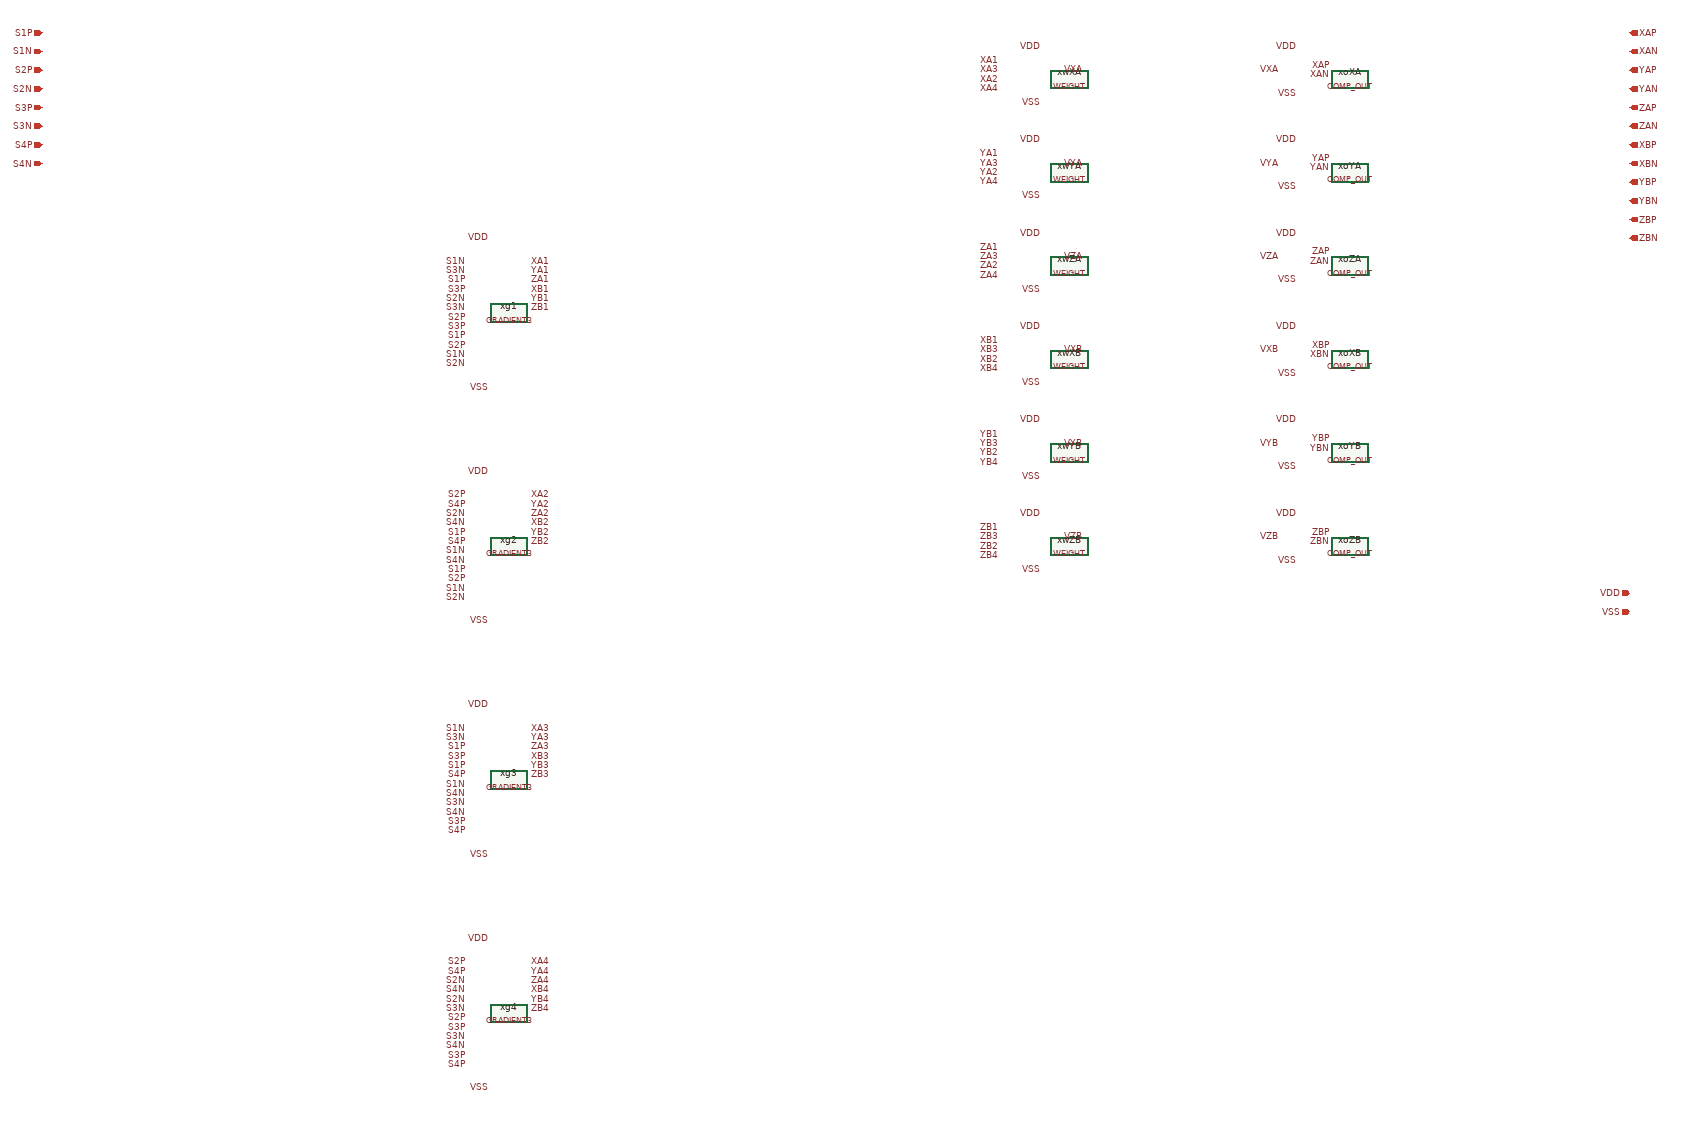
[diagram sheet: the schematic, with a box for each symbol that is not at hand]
v {xschem version=3.4.8RC file_version=1.3}
G {}
K {}
V {}
S {}
F {}
E {}
C {a_zonetic2026/XSCHEM_v2/GRADIENT3.sym} -600 -400 0 0 {name=xg1}
C {devices/lab_pin.sym} -690.0 -510.0 0 0 {name=l1 sig_type=std_logic lab=S1N}
C {devices/lab_pin.sym} -690.0 -490.0 0 0 {name=l2 sig_type=std_logic lab=S3N}
C {devices/lab_pin.sym} -690.0 -470.0 0 0 {name=l3 sig_type=std_logic lab=S1P}
C {devices/lab_pin.sym} -690.0 -450.0 0 0 {name=l4 sig_type=std_logic lab=S3P}
C {devices/lab_pin.sym} -690.0 -430.0 0 0 {name=l5 sig_type=std_logic lab=S2N}
C {devices/lab_pin.sym} -690.0 -410.0 0 0 {name=l6 sig_type=std_logic lab=S3N}
C {devices/lab_pin.sym} -690.0 -390.0 0 0 {name=l7 sig_type=std_logic lab=S2P}
C {devices/lab_pin.sym} -690.0 -370.0 0 0 {name=l8 sig_type=std_logic lab=S3P}
C {devices/lab_pin.sym} -690.0 -350.0 0 0 {name=l9 sig_type=std_logic lab=S1P}
C {devices/lab_pin.sym} -690.0 -330.0 0 0 {name=l10 sig_type=std_logic lab=S2P}
C {devices/lab_pin.sym} -690.0 -310.0 0 0 {name=l11 sig_type=std_logic lab=S1N}
C {devices/lab_pin.sym} -690.0 -290.0 0 0 {name=l12 sig_type=std_logic lab=S2N}
C {devices/lab_pin.sym} -510.0 -510.0 0 0 {name=l13 sig_type=std_logic lab=XA1}
C {devices/lab_pin.sym} -510.0 -490.0 0 0 {name=l14 sig_type=std_logic lab=YA1}
C {devices/lab_pin.sym} -510.0 -470.0 0 0 {name=l15 sig_type=std_logic lab=ZA1}
C {devices/lab_pin.sym} -510.0 -450.0 0 0 {name=l16 sig_type=std_logic lab=XB1}
C {devices/lab_pin.sym} -510.0 -430.0 0 0 {name=l17 sig_type=std_logic lab=YB1}
C {devices/lab_pin.sym} -510.0 -410.0 0 0 {name=l18 sig_type=std_logic lab=ZB1}
C {devices/lab_pin.sym} -640.0 -560.0 0 0 {name=l19 sig_type=std_logic lab=VDD}
C {devices/lab_pin.sym} -640.0 -240.0 0 0 {name=l20 sig_type=std_logic lab=VSS}
C {a_zonetic2026/XSCHEM_v2/GRADIENT3.sym} -600 100 0 0 {name=xg2}
C {devices/lab_pin.sym} -690.0 -10.0 0 0 {name=l21 sig_type=std_logic lab=S2P}
C {devices/lab_pin.sym} -690.0 10.0 0 0 {name=l22 sig_type=std_logic lab=S4P}
C {devices/lab_pin.sym} -690.0 30.0 0 0 {name=l23 sig_type=std_logic lab=S2N}
C {devices/lab_pin.sym} -690.0 50.0 0 0 {name=l24 sig_type=std_logic lab=S4N}
C {devices/lab_pin.sym} -690.0 70.0 0 0 {name=l25 sig_type=std_logic lab=S1P}
C {devices/lab_pin.sym} -690.0 90.0 0 0 {name=l26 sig_type=std_logic lab=S4P}
C {devices/lab_pin.sym} -690.0 110.0 0 0 {name=l27 sig_type=std_logic lab=S1N}
C {devices/lab_pin.sym} -690.0 130.0 0 0 {name=l28 sig_type=std_logic lab=S4N}
C {devices/lab_pin.sym} -690.0 150.0 0 0 {name=l29 sig_type=std_logic lab=S1P}
C {devices/lab_pin.sym} -690.0 170.0 0 0 {name=l30 sig_type=std_logic lab=S2P}
C {devices/lab_pin.sym} -690.0 190.0 0 0 {name=l31 sig_type=std_logic lab=S1N}
C {devices/lab_pin.sym} -690.0 210.0 0 0 {name=l32 sig_type=std_logic lab=S2N}
C {devices/lab_pin.sym} -510.0 -10.0 0 0 {name=l33 sig_type=std_logic lab=XA2}
C {devices/lab_pin.sym} -510.0 10.0 0 0 {name=l34 sig_type=std_logic lab=YA2}
C {devices/lab_pin.sym} -510.0 30.0 0 0 {name=l35 sig_type=std_logic lab=ZA2}
C {devices/lab_pin.sym} -510.0 50.0 0 0 {name=l36 sig_type=std_logic lab=XB2}
C {devices/lab_pin.sym} -510.0 70.0 0 0 {name=l37 sig_type=std_logic lab=YB2}
C {devices/lab_pin.sym} -510.0 90.0 0 0 {name=l38 sig_type=std_logic lab=ZB2}
C {devices/lab_pin.sym} -640.0 -60.0 0 0 {name=l39 sig_type=std_logic lab=VDD}
C {devices/lab_pin.sym} -640.0 260.0 0 0 {name=l40 sig_type=std_logic lab=VSS}
C {a_zonetic2026/XSCHEM_v2/GRADIENT3.sym} -600 600 0 0 {name=xg3}
C {devices/lab_pin.sym} -690.0 490.0 0 0 {name=l41 sig_type=std_logic lab=S1N}
C {devices/lab_pin.sym} -690.0 510.0 0 0 {name=l42 sig_type=std_logic lab=S3N}
C {devices/lab_pin.sym} -690.0 530.0 0 0 {name=l43 sig_type=std_logic lab=S1P}
C {devices/lab_pin.sym} -690.0 550.0 0 0 {name=l44 sig_type=std_logic lab=S3P}
C {devices/lab_pin.sym} -690.0 570.0 0 0 {name=l45 sig_type=std_logic lab=S1P}
C {devices/lab_pin.sym} -690.0 590.0 0 0 {name=l46 sig_type=std_logic lab=S4P}
C {devices/lab_pin.sym} -690.0 610.0 0 0 {name=l47 sig_type=std_logic lab=S1N}
C {devices/lab_pin.sym} -690.0 630.0 0 0 {name=l48 sig_type=std_logic lab=S4N}
C {devices/lab_pin.sym} -690.0 650.0 0 0 {name=l49 sig_type=std_logic lab=S3N}
C {devices/lab_pin.sym} -690.0 670.0 0 0 {name=l50 sig_type=std_logic lab=S4N}
C {devices/lab_pin.sym} -690.0 690.0 0 0 {name=l51 sig_type=std_logic lab=S3P}
C {devices/lab_pin.sym} -690.0 710.0 0 0 {name=l52 sig_type=std_logic lab=S4P}
C {devices/lab_pin.sym} -510.0 490.0 0 0 {name=l53 sig_type=std_logic lab=XA3}
C {devices/lab_pin.sym} -510.0 510.0 0 0 {name=l54 sig_type=std_logic lab=YA3}
C {devices/lab_pin.sym} -510.0 530.0 0 0 {name=l55 sig_type=std_logic lab=ZA3}
C {devices/lab_pin.sym} -510.0 550.0 0 0 {name=l56 sig_type=std_logic lab=XB3}
C {devices/lab_pin.sym} -510.0 570.0 0 0 {name=l57 sig_type=std_logic lab=YB3}
C {devices/lab_pin.sym} -510.0 590.0 0 0 {name=l58 sig_type=std_logic lab=ZB3}
C {devices/lab_pin.sym} -640.0 440.0 0 0 {name=l59 sig_type=std_logic lab=VDD}
C {devices/lab_pin.sym} -640.0 760.0 0 0 {name=l60 sig_type=std_logic lab=VSS}
C {a_zonetic2026/XSCHEM_v2/GRADIENT3.sym} -600 1100 0 0 {name=xg4}
C {devices/lab_pin.sym} -690.0 990.0 0 0 {name=l61 sig_type=std_logic lab=S2P}
C {devices/lab_pin.sym} -690.0 1010.0 0 0 {name=l62 sig_type=std_logic lab=S4P}
C {devices/lab_pin.sym} -690.0 1030.0 0 0 {name=l63 sig_type=std_logic lab=S2N}
C {devices/lab_pin.sym} -690.0 1050.0 0 0 {name=l64 sig_type=std_logic lab=S4N}
C {devices/lab_pin.sym} -690.0 1070.0 0 0 {name=l65 sig_type=std_logic lab=S2N}
C {devices/lab_pin.sym} -690.0 1090.0 0 0 {name=l66 sig_type=std_logic lab=S3N}
C {devices/lab_pin.sym} -690.0 1110.0 0 0 {name=l67 sig_type=std_logic lab=S2P}
C {devices/lab_pin.sym} -690.0 1130.0 0 0 {name=l68 sig_type=std_logic lab=S3P}
C {devices/lab_pin.sym} -690.0 1150.0 0 0 {name=l69 sig_type=std_logic lab=S3N}
C {devices/lab_pin.sym} -690.0 1170.0 0 0 {name=l70 sig_type=std_logic lab=S4N}
C {devices/lab_pin.sym} -690.0 1190.0 0 0 {name=l71 sig_type=std_logic lab=S3P}
C {devices/lab_pin.sym} -690.0 1210.0 0 0 {name=l72 sig_type=std_logic lab=S4P}
C {devices/lab_pin.sym} -510.0 990.0 0 0 {name=l73 sig_type=std_logic lab=XA4}
C {devices/lab_pin.sym} -510.0 1010.0 0 0 {name=l74 sig_type=std_logic lab=YA4}
C {devices/lab_pin.sym} -510.0 1030.0 0 0 {name=l75 sig_type=std_logic lab=ZA4}
C {devices/lab_pin.sym} -510.0 1050.0 0 0 {name=l76 sig_type=std_logic lab=XB4}
C {devices/lab_pin.sym} -510.0 1070.0 0 0 {name=l77 sig_type=std_logic lab=YB4}
C {devices/lab_pin.sym} -510.0 1090.0 0 0 {name=l78 sig_type=std_logic lab=ZB4}
C {devices/lab_pin.sym} -640.0 940.0 0 0 {name=l79 sig_type=std_logic lab=VDD}
C {devices/lab_pin.sym} -640.0 1260.0 0 0 {name=l80 sig_type=std_logic lab=VSS}
C {a_zonetic2026/XSCHEM/WEIGTH/WEIGHT.sym} 600 -900 0 0 {name=xwXA}
C {devices/lab_pin.sym} 540.0 -970.0 0 0 {name=l81 sig_type=std_logic lab=VDD}
C {devices/lab_pin.sym} 540.0 -850.0 0 0 {name=l82 sig_type=std_logic lab=VSS}
C {devices/lab_pin.sym} 630.0 -920.0 0 0 {name=l83 sig_type=std_logic lab=VXA}
C {devices/lab_pin.sym} 450.0 -940.0 0 0 {name=l84 sig_type=std_logic lab=XA1}
C {devices/lab_pin.sym} 450.0 -920.0 0 0 {name=l85 sig_type=std_logic lab=XA3}
C {devices/lab_pin.sym} 450.0 -900.0 0 0 {name=l86 sig_type=std_logic lab=XA2}
C {devices/lab_pin.sym} 450.0 -880.0 0 0 {name=l87 sig_type=std_logic lab=XA4}
C {a_zonetic2026/XSCHEM/WEIGTH/COMP_OUT.sym} 1200 -900 0 0 {name=xoXA}
C {devices/lab_pin.sym} 1090.0 -970.0 0 0 {name=l88 sig_type=std_logic lab=VDD}
C {devices/lab_pin.sym} 1160.0 -930.0 0 0 {name=l89 sig_type=std_logic lab=XAP}
C {devices/lab_pin.sym} 1050.0 -920.0 0 0 {name=l90 sig_type=std_logic lab=VXA}
C {devices/lab_pin.sym} 1160.0 -910.0 0 0 {name=l91 sig_type=std_logic lab=XAN}
C {devices/lab_pin.sym} 1090.0 -870.0 0 0 {name=l92 sig_type=std_logic lab=VSS}
C {a_zonetic2026/XSCHEM/WEIGTH/WEIGHT.sym} 600 -700 0 0 {name=xwYA}
C {devices/lab_pin.sym} 540.0 -770.0 0 0 {name=l93 sig_type=std_logic lab=VDD}
C {devices/lab_pin.sym} 540.0 -650.0 0 0 {name=l94 sig_type=std_logic lab=VSS}
C {devices/lab_pin.sym} 630.0 -720.0 0 0 {name=l95 sig_type=std_logic lab=VYA}
C {devices/lab_pin.sym} 450.0 -740.0 0 0 {name=l96 sig_type=std_logic lab=YA1}
C {devices/lab_pin.sym} 450.0 -720.0 0 0 {name=l97 sig_type=std_logic lab=YA3}
C {devices/lab_pin.sym} 450.0 -700.0 0 0 {name=l98 sig_type=std_logic lab=YA2}
C {devices/lab_pin.sym} 450.0 -680.0 0 0 {name=l99 sig_type=std_logic lab=YA4}
C {a_zonetic2026/XSCHEM/WEIGTH/COMP_OUT.sym} 1200 -700 0 0 {name=xoYA}
C {devices/lab_pin.sym} 1090.0 -770.0 0 0 {name=l100 sig_type=std_logic lab=VDD}
C {devices/lab_pin.sym} 1160.0 -730.0 0 0 {name=l101 sig_type=std_logic lab=YAP}
C {devices/lab_pin.sym} 1050.0 -720.0 0 0 {name=l102 sig_type=std_logic lab=VYA}
C {devices/lab_pin.sym} 1160.0 -710.0 0 0 {name=l103 sig_type=std_logic lab=YAN}
C {devices/lab_pin.sym} 1090.0 -670.0 0 0 {name=l104 sig_type=std_logic lab=VSS}
C {a_zonetic2026/XSCHEM/WEIGTH/WEIGHT.sym} 600 -500 0 0 {name=xwZA}
C {devices/lab_pin.sym} 540.0 -570.0 0 0 {name=l105 sig_type=std_logic lab=VDD}
C {devices/lab_pin.sym} 540.0 -450.0 0 0 {name=l106 sig_type=std_logic lab=VSS}
C {devices/lab_pin.sym} 630.0 -520.0 0 0 {name=l107 sig_type=std_logic lab=VZA}
C {devices/lab_pin.sym} 450.0 -540.0 0 0 {name=l108 sig_type=std_logic lab=ZA1}
C {devices/lab_pin.sym} 450.0 -520.0 0 0 {name=l109 sig_type=std_logic lab=ZA3}
C {devices/lab_pin.sym} 450.0 -500.0 0 0 {name=l110 sig_type=std_logic lab=ZA2}
C {devices/lab_pin.sym} 450.0 -480.0 0 0 {name=l111 sig_type=std_logic lab=ZA4}
C {a_zonetic2026/XSCHEM/WEIGTH/COMP_OUT.sym} 1200 -500 0 0 {name=xoZA}
C {devices/lab_pin.sym} 1090.0 -570.0 0 0 {name=l112 sig_type=std_logic lab=VDD}
C {devices/lab_pin.sym} 1160.0 -530.0 0 0 {name=l113 sig_type=std_logic lab=ZAP}
C {devices/lab_pin.sym} 1050.0 -520.0 0 0 {name=l114 sig_type=std_logic lab=VZA}
C {devices/lab_pin.sym} 1160.0 -510.0 0 0 {name=l115 sig_type=std_logic lab=ZAN}
C {devices/lab_pin.sym} 1090.0 -470.0 0 0 {name=l116 sig_type=std_logic lab=VSS}
C {a_zonetic2026/XSCHEM/WEIGTH/WEIGHT.sym} 600 -300 0 0 {name=xwXB}
C {devices/lab_pin.sym} 540.0 -370.0 0 0 {name=l117 sig_type=std_logic lab=VDD}
C {devices/lab_pin.sym} 540.0 -250.0 0 0 {name=l118 sig_type=std_logic lab=VSS}
C {devices/lab_pin.sym} 630.0 -320.0 0 0 {name=l119 sig_type=std_logic lab=VXB}
C {devices/lab_pin.sym} 450.0 -340.0 0 0 {name=l120 sig_type=std_logic lab=XB1}
C {devices/lab_pin.sym} 450.0 -320.0 0 0 {name=l121 sig_type=std_logic lab=XB3}
C {devices/lab_pin.sym} 450.0 -300.0 0 0 {name=l122 sig_type=std_logic lab=XB2}
C {devices/lab_pin.sym} 450.0 -280.0 0 0 {name=l123 sig_type=std_logic lab=XB4}
C {a_zonetic2026/XSCHEM/WEIGTH/COMP_OUT.sym} 1200 -300 0 0 {name=xoXB}
C {devices/lab_pin.sym} 1090.0 -370.0 0 0 {name=l124 sig_type=std_logic lab=VDD}
C {devices/lab_pin.sym} 1160.0 -330.0 0 0 {name=l125 sig_type=std_logic lab=XBP}
C {devices/lab_pin.sym} 1050.0 -320.0 0 0 {name=l126 sig_type=std_logic lab=VXB}
C {devices/lab_pin.sym} 1160.0 -310.0 0 0 {name=l127 sig_type=std_logic lab=XBN}
C {devices/lab_pin.sym} 1090.0 -270.0 0 0 {name=l128 sig_type=std_logic lab=VSS}
C {a_zonetic2026/XSCHEM/WEIGTH/WEIGHT.sym} 600 -100 0 0 {name=xwYB}
C {devices/lab_pin.sym} 540.0 -170.0 0 0 {name=l129 sig_type=std_logic lab=VDD}
C {devices/lab_pin.sym} 540.0 -50.0 0 0 {name=l130 sig_type=std_logic lab=VSS}
C {devices/lab_pin.sym} 630.0 -120.0 0 0 {name=l131 sig_type=std_logic lab=VYB}
C {devices/lab_pin.sym} 450.0 -140.0 0 0 {name=l132 sig_type=std_logic lab=YB1}
C {devices/lab_pin.sym} 450.0 -120.0 0 0 {name=l133 sig_type=std_logic lab=YB3}
C {devices/lab_pin.sym} 450.0 -100.0 0 0 {name=l134 sig_type=std_logic lab=YB2}
C {devices/lab_pin.sym} 450.0 -80.0 0 0 {name=l135 sig_type=std_logic lab=YB4}
C {a_zonetic2026/XSCHEM/WEIGTH/COMP_OUT.sym} 1200 -100 0 0 {name=xoYB}
C {devices/lab_pin.sym} 1090.0 -170.0 0 0 {name=l136 sig_type=std_logic lab=VDD}
C {devices/lab_pin.sym} 1160.0 -130.0 0 0 {name=l137 sig_type=std_logic lab=YBP}
C {devices/lab_pin.sym} 1050.0 -120.0 0 0 {name=l138 sig_type=std_logic lab=VYB}
C {devices/lab_pin.sym} 1160.0 -110.0 0 0 {name=l139 sig_type=std_logic lab=YBN}
C {devices/lab_pin.sym} 1090.0 -70.0 0 0 {name=l140 sig_type=std_logic lab=VSS}
C {a_zonetic2026/XSCHEM/WEIGTH/WEIGHT.sym} 600 100 0 0 {name=xwZB}
C {devices/lab_pin.sym} 540.0 30.0 0 0 {name=l141 sig_type=std_logic lab=VDD}
C {devices/lab_pin.sym} 540.0 150.0 0 0 {name=l142 sig_type=std_logic lab=VSS}
C {devices/lab_pin.sym} 630.0 80.0 0 0 {name=l143 sig_type=std_logic lab=VZB}
C {devices/lab_pin.sym} 450.0 60.0 0 0 {name=l144 sig_type=std_logic lab=ZB1}
C {devices/lab_pin.sym} 450.0 80.0 0 0 {name=l145 sig_type=std_logic lab=ZB3}
C {devices/lab_pin.sym} 450.0 100.0 0 0 {name=l146 sig_type=std_logic lab=ZB2}
C {devices/lab_pin.sym} 450.0 120.0 0 0 {name=l147 sig_type=std_logic lab=ZB4}
C {a_zonetic2026/XSCHEM/WEIGTH/COMP_OUT.sym} 1200 100 0 0 {name=xoZB}
C {devices/lab_pin.sym} 1090.0 30.0 0 0 {name=l148 sig_type=std_logic lab=VDD}
C {devices/lab_pin.sym} 1160.0 70.0 0 0 {name=l149 sig_type=std_logic lab=ZBP}
C {devices/lab_pin.sym} 1050.0 80.0 0 0 {name=l150 sig_type=std_logic lab=VZB}
C {devices/lab_pin.sym} 1160.0 90.0 0 0 {name=l151 sig_type=std_logic lab=ZBN}
C {devices/lab_pin.sym} 1090.0 130.0 0 0 {name=l152 sig_type=std_logic lab=VSS}
C {ipin.sym} -1600 -1000 0 0 {name=q153 lab=S1P}
C {ipin.sym} -1600 -960 0 0 {name=q154 lab=S1N}
C {ipin.sym} -1600 -920 0 0 {name=q155 lab=S2P}
C {ipin.sym} -1600 -880 0 0 {name=q156 lab=S2N}
C {ipin.sym} -1600 -840 0 0 {name=q157 lab=S3P}
C {ipin.sym} -1600 -800 0 0 {name=q158 lab=S3N}
C {ipin.sym} -1600 -760 0 0 {name=q159 lab=S4P}
C {ipin.sym} -1600 -720 0 0 {name=q160 lab=S4N}
C {opin.sym} 1800 -1000 0 0 {name=q161 lab=XAP}
C {opin.sym} 1800 -960 0 0 {name=q162 lab=XAN}
C {opin.sym} 1800 -920 0 0 {name=q163 lab=YAP}
C {opin.sym} 1800 -880 0 0 {name=q164 lab=YAN}
C {opin.sym} 1800 -840 0 0 {name=q165 lab=ZAP}
C {opin.sym} 1800 -800 0 0 {name=q166 lab=ZAN}
C {opin.sym} 1800 -760 0 0 {name=q167 lab=XBP}
C {opin.sym} 1800 -720 0 0 {name=q168 lab=XBN}
C {opin.sym} 1800 -680 0 0 {name=q169 lab=YBP}
C {opin.sym} 1800 -640 0 0 {name=q170 lab=YBN}
C {opin.sym} 1800 -600 0 0 {name=q171 lab=ZBP}
C {opin.sym} 1800 -560 0 0 {name=q172 lab=ZBN}
C {iopin.sym} 1800 200 0 0 {name=q173 lab=VDD}
C {iopin.sym} 1800 240 0 0 {name=q174 lab=VSS}
